VERSION 5.7 ;
BUSBITCHARS "[]" ;
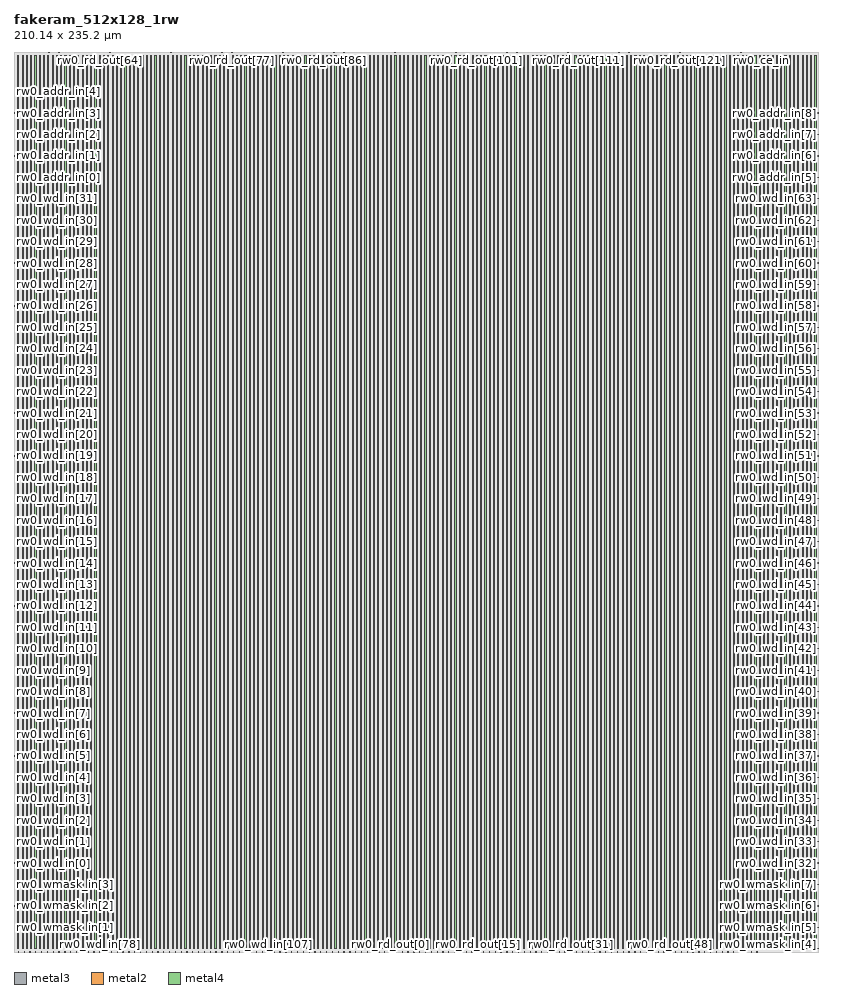
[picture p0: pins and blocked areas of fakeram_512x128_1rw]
MACRO fakeram_512x128_1rw
  FOREIGN fakeram_512x128_1rw 0 0 ;
  SYMMETRY X Y R90 ;
  SIZE 210.140 BY 235.200 ;
  CLASS BLOCK ;
  PIN rw0_wmask_in[0]
    DIRECTION INPUT ;
    USE SIGNAL ;
    SHAPE ABUTMENT ;
    PORT
      LAYER metal3 ;
      RECT 0.000 0.805 0.210 0.875 ;
    END
  END rw0_wmask_in[0]
  PIN rw0_wmask_in[1]
    DIRECTION INPUT ;
    USE SIGNAL ;
    SHAPE ABUTMENT ;
    PORT
      LAYER metal3 ;
      RECT 0.000 6.405 0.210 6.475 ;
    END
  END rw0_wmask_in[1]
  PIN rw0_wmask_in[2]
    DIRECTION INPUT ;
    USE SIGNAL ;
    SHAPE ABUTMENT ;
    PORT
      LAYER metal3 ;
      RECT 0.000 12.005 0.210 12.075 ;
    END
  END rw0_wmask_in[2]
  PIN rw0_wmask_in[3]
    DIRECTION INPUT ;
    USE SIGNAL ;
    SHAPE ABUTMENT ;
    PORT
      LAYER metal3 ;
      RECT 0.000 17.605 0.210 17.675 ;
    END
  END rw0_wmask_in[3]
  PIN rw0_wmask_in[4]
    DIRECTION INPUT ;
    USE SIGNAL ;
    SHAPE ABUTMENT ;
    PORT
      LAYER metal3 ;
      RECT 209.930 0.805 210.140 0.875 ;
    END
  END rw0_wmask_in[4]
  PIN rw0_wmask_in[5]
    DIRECTION INPUT ;
    USE SIGNAL ;
    SHAPE ABUTMENT ;
    PORT
      LAYER metal3 ;
      RECT 209.930 6.405 210.140 6.475 ;
    END
  END rw0_wmask_in[5]
  PIN rw0_wmask_in[6]
    DIRECTION INPUT ;
    USE SIGNAL ;
    SHAPE ABUTMENT ;
    PORT
      LAYER metal3 ;
      RECT 209.930 12.005 210.140 12.075 ;
    END
  END rw0_wmask_in[6]
  PIN rw0_wmask_in[7]
    DIRECTION INPUT ;
    USE SIGNAL ;
    SHAPE ABUTMENT ;
    PORT
      LAYER metal3 ;
      RECT 209.930 17.605 210.140 17.675 ;
    END
  END rw0_wmask_in[7]
  PIN rw0_wmask_in[8]
    DIRECTION INPUT ;
    USE SIGNAL ;
    SHAPE ABUTMENT ;
    PORT
      LAYER metal2 ;
      RECT 1.105 234.990 1.175 235.200 ;
    END
  END rw0_wmask_in[8]
  PIN rw0_wmask_in[9]
    DIRECTION INPUT ;
    USE SIGNAL ;
    SHAPE ABUTMENT ;
    PORT
      LAYER metal2 ;
      RECT 3.765 234.990 3.835 235.200 ;
    END
  END rw0_wmask_in[9]
  PIN rw0_wmask_in[10]
    DIRECTION INPUT ;
    USE SIGNAL ;
    SHAPE ABUTMENT ;
    PORT
      LAYER metal2 ;
      RECT 6.425 234.990 6.495 235.200 ;
    END
  END rw0_wmask_in[10]
  PIN rw0_wmask_in[11]
    DIRECTION INPUT ;
    USE SIGNAL ;
    SHAPE ABUTMENT ;
    PORT
      LAYER metal2 ;
      RECT 9.085 234.990 9.155 235.200 ;
    END
  END rw0_wmask_in[11]
  PIN rw0_wmask_in[12]
    DIRECTION INPUT ;
    USE SIGNAL ;
    SHAPE ABUTMENT ;
    PORT
      LAYER metal2 ;
      RECT 11.745 234.990 11.815 235.200 ;
    END
  END rw0_wmask_in[12]
  PIN rw0_wmask_in[13]
    DIRECTION INPUT ;
    USE SIGNAL ;
    SHAPE ABUTMENT ;
    PORT
      LAYER metal2 ;
      RECT 14.405 234.990 14.475 235.200 ;
    END
  END rw0_wmask_in[13]
  PIN rw0_wmask_in[14]
    DIRECTION INPUT ;
    USE SIGNAL ;
    SHAPE ABUTMENT ;
    PORT
      LAYER metal2 ;
      RECT 17.065 234.990 17.135 235.200 ;
    END
  END rw0_wmask_in[14]
  PIN rw0_wmask_in[15]
    DIRECTION INPUT ;
    USE SIGNAL ;
    SHAPE ABUTMENT ;
    PORT
      LAYER metal2 ;
      RECT 19.725 234.990 19.795 235.200 ;
    END
  END rw0_wmask_in[15]
  PIN rw0_wd_in[0]
    DIRECTION INPUT ;
    USE SIGNAL ;
    SHAPE ABUTMENT ;
    PORT
      LAYER metal3 ;
      RECT 0.000 23.205 0.210 23.275 ;
    END
  END rw0_wd_in[0]
  PIN rw0_wd_in[1]
    DIRECTION INPUT ;
    USE SIGNAL ;
    SHAPE ABUTMENT ;
    PORT
      LAYER metal3 ;
      RECT 0.000 28.805 0.210 28.875 ;
    END
  END rw0_wd_in[1]
  PIN rw0_wd_in[2]
    DIRECTION INPUT ;
    USE SIGNAL ;
    SHAPE ABUTMENT ;
    PORT
      LAYER metal3 ;
      RECT 0.000 34.405 0.210 34.475 ;
    END
  END rw0_wd_in[2]
  PIN rw0_wd_in[3]
    DIRECTION INPUT ;
    USE SIGNAL ;
    SHAPE ABUTMENT ;
    PORT
      LAYER metal3 ;
      RECT 0.000 40.005 0.210 40.075 ;
    END
  END rw0_wd_in[3]
  PIN rw0_wd_in[4]
    DIRECTION INPUT ;
    USE SIGNAL ;
    SHAPE ABUTMENT ;
    PORT
      LAYER metal3 ;
      RECT 0.000 45.605 0.210 45.675 ;
    END
  END rw0_wd_in[4]
  PIN rw0_wd_in[5]
    DIRECTION INPUT ;
    USE SIGNAL ;
    SHAPE ABUTMENT ;
    PORT
      LAYER metal3 ;
      RECT 0.000 51.205 0.210 51.275 ;
    END
  END rw0_wd_in[5]
  PIN rw0_wd_in[6]
    DIRECTION INPUT ;
    USE SIGNAL ;
    SHAPE ABUTMENT ;
    PORT
      LAYER metal3 ;
      RECT 0.000 56.805 0.210 56.875 ;
    END
  END rw0_wd_in[6]
  PIN rw0_wd_in[7]
    DIRECTION INPUT ;
    USE SIGNAL ;
    SHAPE ABUTMENT ;
    PORT
      LAYER metal3 ;
      RECT 0.000 62.405 0.210 62.475 ;
    END
  END rw0_wd_in[7]
  PIN rw0_wd_in[8]
    DIRECTION INPUT ;
    USE SIGNAL ;
    SHAPE ABUTMENT ;
    PORT
      LAYER metal3 ;
      RECT 0.000 68.005 0.210 68.075 ;
    END
  END rw0_wd_in[8]
  PIN rw0_wd_in[9]
    DIRECTION INPUT ;
    USE SIGNAL ;
    SHAPE ABUTMENT ;
    PORT
      LAYER metal3 ;
      RECT 0.000 73.605 0.210 73.675 ;
    END
  END rw0_wd_in[9]
  PIN rw0_wd_in[10]
    DIRECTION INPUT ;
    USE SIGNAL ;
    SHAPE ABUTMENT ;
    PORT
      LAYER metal3 ;
      RECT 0.000 79.205 0.210 79.275 ;
    END
  END rw0_wd_in[10]
  PIN rw0_wd_in[11]
    DIRECTION INPUT ;
    USE SIGNAL ;
    SHAPE ABUTMENT ;
    PORT
      LAYER metal3 ;
      RECT 0.000 84.805 0.210 84.875 ;
    END
  END rw0_wd_in[11]
  PIN rw0_wd_in[12]
    DIRECTION INPUT ;
    USE SIGNAL ;
    SHAPE ABUTMENT ;
    PORT
      LAYER metal3 ;
      RECT 0.000 90.405 0.210 90.475 ;
    END
  END rw0_wd_in[12]
  PIN rw0_wd_in[13]
    DIRECTION INPUT ;
    USE SIGNAL ;
    SHAPE ABUTMENT ;
    PORT
      LAYER metal3 ;
      RECT 0.000 96.005 0.210 96.075 ;
    END
  END rw0_wd_in[13]
  PIN rw0_wd_in[14]
    DIRECTION INPUT ;
    USE SIGNAL ;
    SHAPE ABUTMENT ;
    PORT
      LAYER metal3 ;
      RECT 0.000 101.605 0.210 101.675 ;
    END
  END rw0_wd_in[14]
  PIN rw0_wd_in[15]
    DIRECTION INPUT ;
    USE SIGNAL ;
    SHAPE ABUTMENT ;
    PORT
      LAYER metal3 ;
      RECT 0.000 107.205 0.210 107.275 ;
    END
  END rw0_wd_in[15]
  PIN rw0_wd_in[16]
    DIRECTION INPUT ;
    USE SIGNAL ;
    SHAPE ABUTMENT ;
    PORT
      LAYER metal3 ;
      RECT 0.000 112.805 0.210 112.875 ;
    END
  END rw0_wd_in[16]
  PIN rw0_wd_in[17]
    DIRECTION INPUT ;
    USE SIGNAL ;
    SHAPE ABUTMENT ;
    PORT
      LAYER metal3 ;
      RECT 0.000 118.405 0.210 118.475 ;
    END
  END rw0_wd_in[17]
  PIN rw0_wd_in[18]
    DIRECTION INPUT ;
    USE SIGNAL ;
    SHAPE ABUTMENT ;
    PORT
      LAYER metal3 ;
      RECT 0.000 124.005 0.210 124.075 ;
    END
  END rw0_wd_in[18]
  PIN rw0_wd_in[19]
    DIRECTION INPUT ;
    USE SIGNAL ;
    SHAPE ABUTMENT ;
    PORT
      LAYER metal3 ;
      RECT 0.000 129.605 0.210 129.675 ;
    END
  END rw0_wd_in[19]
  PIN rw0_wd_in[20]
    DIRECTION INPUT ;
    USE SIGNAL ;
    SHAPE ABUTMENT ;
    PORT
      LAYER metal3 ;
      RECT 0.000 135.205 0.210 135.275 ;
    END
  END rw0_wd_in[20]
  PIN rw0_wd_in[21]
    DIRECTION INPUT ;
    USE SIGNAL ;
    SHAPE ABUTMENT ;
    PORT
      LAYER metal3 ;
      RECT 0.000 140.805 0.210 140.875 ;
    END
  END rw0_wd_in[21]
  PIN rw0_wd_in[22]
    DIRECTION INPUT ;
    USE SIGNAL ;
    SHAPE ABUTMENT ;
    PORT
      LAYER metal3 ;
      RECT 0.000 146.405 0.210 146.475 ;
    END
  END rw0_wd_in[22]
  PIN rw0_wd_in[23]
    DIRECTION INPUT ;
    USE SIGNAL ;
    SHAPE ABUTMENT ;
    PORT
      LAYER metal3 ;
      RECT 0.000 152.005 0.210 152.075 ;
    END
  END rw0_wd_in[23]
  PIN rw0_wd_in[24]
    DIRECTION INPUT ;
    USE SIGNAL ;
    SHAPE ABUTMENT ;
    PORT
      LAYER metal3 ;
      RECT 0.000 157.605 0.210 157.675 ;
    END
  END rw0_wd_in[24]
  PIN rw0_wd_in[25]
    DIRECTION INPUT ;
    USE SIGNAL ;
    SHAPE ABUTMENT ;
    PORT
      LAYER metal3 ;
      RECT 0.000 163.205 0.210 163.275 ;
    END
  END rw0_wd_in[25]
  PIN rw0_wd_in[26]
    DIRECTION INPUT ;
    USE SIGNAL ;
    SHAPE ABUTMENT ;
    PORT
      LAYER metal3 ;
      RECT 0.000 168.805 0.210 168.875 ;
    END
  END rw0_wd_in[26]
  PIN rw0_wd_in[27]
    DIRECTION INPUT ;
    USE SIGNAL ;
    SHAPE ABUTMENT ;
    PORT
      LAYER metal3 ;
      RECT 0.000 174.405 0.210 174.475 ;
    END
  END rw0_wd_in[27]
  PIN rw0_wd_in[28]
    DIRECTION INPUT ;
    USE SIGNAL ;
    SHAPE ABUTMENT ;
    PORT
      LAYER metal3 ;
      RECT 0.000 180.005 0.210 180.075 ;
    END
  END rw0_wd_in[28]
  PIN rw0_wd_in[29]
    DIRECTION INPUT ;
    USE SIGNAL ;
    SHAPE ABUTMENT ;
    PORT
      LAYER metal3 ;
      RECT 0.000 185.605 0.210 185.675 ;
    END
  END rw0_wd_in[29]
  PIN rw0_wd_in[30]
    DIRECTION INPUT ;
    USE SIGNAL ;
    SHAPE ABUTMENT ;
    PORT
      LAYER metal3 ;
      RECT 0.000 191.205 0.210 191.275 ;
    END
  END rw0_wd_in[30]
  PIN rw0_wd_in[31]
    DIRECTION INPUT ;
    USE SIGNAL ;
    SHAPE ABUTMENT ;
    PORT
      LAYER metal3 ;
      RECT 0.000 196.805 0.210 196.875 ;
    END
  END rw0_wd_in[31]
  PIN rw0_wd_in[32]
    DIRECTION INPUT ;
    USE SIGNAL ;
    SHAPE ABUTMENT ;
    PORT
      LAYER metal3 ;
      RECT 209.930 23.205 210.140 23.275 ;
    END
  END rw0_wd_in[32]
  PIN rw0_wd_in[33]
    DIRECTION INPUT ;
    USE SIGNAL ;
    SHAPE ABUTMENT ;
    PORT
      LAYER metal3 ;
      RECT 209.930 28.805 210.140 28.875 ;
    END
  END rw0_wd_in[33]
  PIN rw0_wd_in[34]
    DIRECTION INPUT ;
    USE SIGNAL ;
    SHAPE ABUTMENT ;
    PORT
      LAYER metal3 ;
      RECT 209.930 34.405 210.140 34.475 ;
    END
  END rw0_wd_in[34]
  PIN rw0_wd_in[35]
    DIRECTION INPUT ;
    USE SIGNAL ;
    SHAPE ABUTMENT ;
    PORT
      LAYER metal3 ;
      RECT 209.930 40.005 210.140 40.075 ;
    END
  END rw0_wd_in[35]
  PIN rw0_wd_in[36]
    DIRECTION INPUT ;
    USE SIGNAL ;
    SHAPE ABUTMENT ;
    PORT
      LAYER metal3 ;
      RECT 209.930 45.605 210.140 45.675 ;
    END
  END rw0_wd_in[36]
  PIN rw0_wd_in[37]
    DIRECTION INPUT ;
    USE SIGNAL ;
    SHAPE ABUTMENT ;
    PORT
      LAYER metal3 ;
      RECT 209.930 51.205 210.140 51.275 ;
    END
  END rw0_wd_in[37]
  PIN rw0_wd_in[38]
    DIRECTION INPUT ;
    USE SIGNAL ;
    SHAPE ABUTMENT ;
    PORT
      LAYER metal3 ;
      RECT 209.930 56.805 210.140 56.875 ;
    END
  END rw0_wd_in[38]
  PIN rw0_wd_in[39]
    DIRECTION INPUT ;
    USE SIGNAL ;
    SHAPE ABUTMENT ;
    PORT
      LAYER metal3 ;
      RECT 209.930 62.405 210.140 62.475 ;
    END
  END rw0_wd_in[39]
  PIN rw0_wd_in[40]
    DIRECTION INPUT ;
    USE SIGNAL ;
    SHAPE ABUTMENT ;
    PORT
      LAYER metal3 ;
      RECT 209.930 68.005 210.140 68.075 ;
    END
  END rw0_wd_in[40]
  PIN rw0_wd_in[41]
    DIRECTION INPUT ;
    USE SIGNAL ;
    SHAPE ABUTMENT ;
    PORT
      LAYER metal3 ;
      RECT 209.930 73.605 210.140 73.675 ;
    END
  END rw0_wd_in[41]
  PIN rw0_wd_in[42]
    DIRECTION INPUT ;
    USE SIGNAL ;
    SHAPE ABUTMENT ;
    PORT
      LAYER metal3 ;
      RECT 209.930 79.205 210.140 79.275 ;
    END
  END rw0_wd_in[42]
  PIN rw0_wd_in[43]
    DIRECTION INPUT ;
    USE SIGNAL ;
    SHAPE ABUTMENT ;
    PORT
      LAYER metal3 ;
      RECT 209.930 84.805 210.140 84.875 ;
    END
  END rw0_wd_in[43]
  PIN rw0_wd_in[44]
    DIRECTION INPUT ;
    USE SIGNAL ;
    SHAPE ABUTMENT ;
    PORT
      LAYER metal3 ;
      RECT 209.930 90.405 210.140 90.475 ;
    END
  END rw0_wd_in[44]
  PIN rw0_wd_in[45]
    DIRECTION INPUT ;
    USE SIGNAL ;
    SHAPE ABUTMENT ;
    PORT
      LAYER metal3 ;
      RECT 209.930 96.005 210.140 96.075 ;
    END
  END rw0_wd_in[45]
  PIN rw0_wd_in[46]
    DIRECTION INPUT ;
    USE SIGNAL ;
    SHAPE ABUTMENT ;
    PORT
      LAYER metal3 ;
      RECT 209.930 101.605 210.140 101.675 ;
    END
  END rw0_wd_in[46]
  PIN rw0_wd_in[47]
    DIRECTION INPUT ;
    USE SIGNAL ;
    SHAPE ABUTMENT ;
    PORT
      LAYER metal3 ;
      RECT 209.930 107.205 210.140 107.275 ;
    END
  END rw0_wd_in[47]
  PIN rw0_wd_in[48]
    DIRECTION INPUT ;
    USE SIGNAL ;
    SHAPE ABUTMENT ;
    PORT
      LAYER metal3 ;
      RECT 209.930 112.805 210.140 112.875 ;
    END
  END rw0_wd_in[48]
  PIN rw0_wd_in[49]
    DIRECTION INPUT ;
    USE SIGNAL ;
    SHAPE ABUTMENT ;
    PORT
      LAYER metal3 ;
      RECT 209.930 118.405 210.140 118.475 ;
    END
  END rw0_wd_in[49]
  PIN rw0_wd_in[50]
    DIRECTION INPUT ;
    USE SIGNAL ;
    SHAPE ABUTMENT ;
    PORT
      LAYER metal3 ;
      RECT 209.930 124.005 210.140 124.075 ;
    END
  END rw0_wd_in[50]
  PIN rw0_wd_in[51]
    DIRECTION INPUT ;
    USE SIGNAL ;
    SHAPE ABUTMENT ;
    PORT
      LAYER metal3 ;
      RECT 209.930 129.605 210.140 129.675 ;
    END
  END rw0_wd_in[51]
  PIN rw0_wd_in[52]
    DIRECTION INPUT ;
    USE SIGNAL ;
    SHAPE ABUTMENT ;
    PORT
      LAYER metal3 ;
      RECT 209.930 135.205 210.140 135.275 ;
    END
  END rw0_wd_in[52]
  PIN rw0_wd_in[53]
    DIRECTION INPUT ;
    USE SIGNAL ;
    SHAPE ABUTMENT ;
    PORT
      LAYER metal3 ;
      RECT 209.930 140.805 210.140 140.875 ;
    END
  END rw0_wd_in[53]
  PIN rw0_wd_in[54]
    DIRECTION INPUT ;
    USE SIGNAL ;
    SHAPE ABUTMENT ;
    PORT
      LAYER metal3 ;
      RECT 209.930 146.405 210.140 146.475 ;
    END
  END rw0_wd_in[54]
  PIN rw0_wd_in[55]
    DIRECTION INPUT ;
    USE SIGNAL ;
    SHAPE ABUTMENT ;
    PORT
      LAYER metal3 ;
      RECT 209.930 152.005 210.140 152.075 ;
    END
  END rw0_wd_in[55]
  PIN rw0_wd_in[56]
    DIRECTION INPUT ;
    USE SIGNAL ;
    SHAPE ABUTMENT ;
    PORT
      LAYER metal3 ;
      RECT 209.930 157.605 210.140 157.675 ;
    END
  END rw0_wd_in[56]
  PIN rw0_wd_in[57]
    DIRECTION INPUT ;
    USE SIGNAL ;
    SHAPE ABUTMENT ;
    PORT
      LAYER metal3 ;
      RECT 209.930 163.205 210.140 163.275 ;
    END
  END rw0_wd_in[57]
  PIN rw0_wd_in[58]
    DIRECTION INPUT ;
    USE SIGNAL ;
    SHAPE ABUTMENT ;
    PORT
      LAYER metal3 ;
      RECT 209.930 168.805 210.140 168.875 ;
    END
  END rw0_wd_in[58]
  PIN rw0_wd_in[59]
    DIRECTION INPUT ;
    USE SIGNAL ;
    SHAPE ABUTMENT ;
    PORT
      LAYER metal3 ;
      RECT 209.930 174.405 210.140 174.475 ;
    END
  END rw0_wd_in[59]
  PIN rw0_wd_in[60]
    DIRECTION INPUT ;
    USE SIGNAL ;
    SHAPE ABUTMENT ;
    PORT
      LAYER metal3 ;
      RECT 209.930 180.005 210.140 180.075 ;
    END
  END rw0_wd_in[60]
  PIN rw0_wd_in[61]
    DIRECTION INPUT ;
    USE SIGNAL ;
    SHAPE ABUTMENT ;
    PORT
      LAYER metal3 ;
      RECT 209.930 185.605 210.140 185.675 ;
    END
  END rw0_wd_in[61]
  PIN rw0_wd_in[62]
    DIRECTION INPUT ;
    USE SIGNAL ;
    SHAPE ABUTMENT ;
    PORT
      LAYER metal3 ;
      RECT 209.930 191.205 210.140 191.275 ;
    END
  END rw0_wd_in[62]
  PIN rw0_wd_in[63]
    DIRECTION INPUT ;
    USE SIGNAL ;
    SHAPE ABUTMENT ;
    PORT
      LAYER metal3 ;
      RECT 209.930 196.805 210.140 196.875 ;
    END
  END rw0_wd_in[63]
  PIN rw0_wd_in[64]
    DIRECTION INPUT ;
    USE SIGNAL ;
    SHAPE ABUTMENT ;
    PORT
      LAYER metal2 ;
      RECT 1.105 0.000 1.175 0.210 ;
    END
  END rw0_wd_in[64]
  PIN rw0_wd_in[65]
    DIRECTION INPUT ;
    USE SIGNAL ;
    SHAPE ABUTMENT ;
    PORT
      LAYER metal2 ;
      RECT 2.625 0.000 2.695 0.210 ;
    END
  END rw0_wd_in[65]
  PIN rw0_wd_in[66]
    DIRECTION INPUT ;
    USE SIGNAL ;
    SHAPE ABUTMENT ;
    PORT
      LAYER metal2 ;
      RECT 4.145 0.000 4.215 0.210 ;
    END
  END rw0_wd_in[66]
  PIN rw0_wd_in[67]
    DIRECTION INPUT ;
    USE SIGNAL ;
    SHAPE ABUTMENT ;
    PORT
      LAYER metal2 ;
      RECT 5.665 0.000 5.735 0.210 ;
    END
  END rw0_wd_in[67]
  PIN rw0_wd_in[68]
    DIRECTION INPUT ;
    USE SIGNAL ;
    SHAPE ABUTMENT ;
    PORT
      LAYER metal2 ;
      RECT 7.185 0.000 7.255 0.210 ;
    END
  END rw0_wd_in[68]
  PIN rw0_wd_in[69]
    DIRECTION INPUT ;
    USE SIGNAL ;
    SHAPE ABUTMENT ;
    PORT
      LAYER metal2 ;
      RECT 8.705 0.000 8.775 0.210 ;
    END
  END rw0_wd_in[69]
  PIN rw0_wd_in[70]
    DIRECTION INPUT ;
    USE SIGNAL ;
    SHAPE ABUTMENT ;
    PORT
      LAYER metal2 ;
      RECT 10.225 0.000 10.295 0.210 ;
    END
  END rw0_wd_in[70]
  PIN rw0_wd_in[71]
    DIRECTION INPUT ;
    USE SIGNAL ;
    SHAPE ABUTMENT ;
    PORT
      LAYER metal2 ;
      RECT 11.745 0.000 11.815 0.210 ;
    END
  END rw0_wd_in[71]
  PIN rw0_wd_in[72]
    DIRECTION INPUT ;
    USE SIGNAL ;
    SHAPE ABUTMENT ;
    PORT
      LAYER metal2 ;
      RECT 13.265 0.000 13.335 0.210 ;
    END
  END rw0_wd_in[72]
  PIN rw0_wd_in[73]
    DIRECTION INPUT ;
    USE SIGNAL ;
    SHAPE ABUTMENT ;
    PORT
      LAYER metal2 ;
      RECT 14.785 0.000 14.855 0.210 ;
    END
  END rw0_wd_in[73]
  PIN rw0_wd_in[74]
    DIRECTION INPUT ;
    USE SIGNAL ;
    SHAPE ABUTMENT ;
    PORT
      LAYER metal2 ;
      RECT 16.305 0.000 16.375 0.210 ;
    END
  END rw0_wd_in[74]
  PIN rw0_wd_in[75]
    DIRECTION INPUT ;
    USE SIGNAL ;
    SHAPE ABUTMENT ;
    PORT
      LAYER metal2 ;
      RECT 17.825 0.000 17.895 0.210 ;
    END
  END rw0_wd_in[75]
  PIN rw0_wd_in[76]
    DIRECTION INPUT ;
    USE SIGNAL ;
    SHAPE ABUTMENT ;
    PORT
      LAYER metal2 ;
      RECT 19.345 0.000 19.415 0.210 ;
    END
  END rw0_wd_in[76]
  PIN rw0_wd_in[77]
    DIRECTION INPUT ;
    USE SIGNAL ;
    SHAPE ABUTMENT ;
    PORT
      LAYER metal2 ;
      RECT 20.865 0.000 20.935 0.210 ;
    END
  END rw0_wd_in[77]
  PIN rw0_wd_in[78]
    DIRECTION INPUT ;
    USE SIGNAL ;
    SHAPE ABUTMENT ;
    PORT
      LAYER metal2 ;
      RECT 22.385 0.000 22.455 0.210 ;
    END
  END rw0_wd_in[78]
  PIN rw0_wd_in[79]
    DIRECTION INPUT ;
    USE SIGNAL ;
    SHAPE ABUTMENT ;
    PORT
      LAYER metal2 ;
      RECT 23.905 0.000 23.975 0.210 ;
    END
  END rw0_wd_in[79]
  PIN rw0_wd_in[80]
    DIRECTION INPUT ;
    USE SIGNAL ;
    SHAPE ABUTMENT ;
    PORT
      LAYER metal2 ;
      RECT 25.425 0.000 25.495 0.210 ;
    END
  END rw0_wd_in[80]
  PIN rw0_wd_in[81]
    DIRECTION INPUT ;
    USE SIGNAL ;
    SHAPE ABUTMENT ;
    PORT
      LAYER metal2 ;
      RECT 26.945 0.000 27.015 0.210 ;
    END
  END rw0_wd_in[81]
  PIN rw0_wd_in[82]
    DIRECTION INPUT ;
    USE SIGNAL ;
    SHAPE ABUTMENT ;
    PORT
      LAYER metal2 ;
      RECT 28.465 0.000 28.535 0.210 ;
    END
  END rw0_wd_in[82]
  PIN rw0_wd_in[83]
    DIRECTION INPUT ;
    USE SIGNAL ;
    SHAPE ABUTMENT ;
    PORT
      LAYER metal2 ;
      RECT 29.985 0.000 30.055 0.210 ;
    END
  END rw0_wd_in[83]
  PIN rw0_wd_in[84]
    DIRECTION INPUT ;
    USE SIGNAL ;
    SHAPE ABUTMENT ;
    PORT
      LAYER metal2 ;
      RECT 31.505 0.000 31.575 0.210 ;
    END
  END rw0_wd_in[84]
  PIN rw0_wd_in[85]
    DIRECTION INPUT ;
    USE SIGNAL ;
    SHAPE ABUTMENT ;
    PORT
      LAYER metal2 ;
      RECT 33.025 0.000 33.095 0.210 ;
    END
  END rw0_wd_in[85]
  PIN rw0_wd_in[86]
    DIRECTION INPUT ;
    USE SIGNAL ;
    SHAPE ABUTMENT ;
    PORT
      LAYER metal2 ;
      RECT 34.545 0.000 34.615 0.210 ;
    END
  END rw0_wd_in[86]
  PIN rw0_wd_in[87]
    DIRECTION INPUT ;
    USE SIGNAL ;
    SHAPE ABUTMENT ;
    PORT
      LAYER metal2 ;
      RECT 36.065 0.000 36.135 0.210 ;
    END
  END rw0_wd_in[87]
  PIN rw0_wd_in[88]
    DIRECTION INPUT ;
    USE SIGNAL ;
    SHAPE ABUTMENT ;
    PORT
      LAYER metal2 ;
      RECT 37.585 0.000 37.655 0.210 ;
    END
  END rw0_wd_in[88]
  PIN rw0_wd_in[89]
    DIRECTION INPUT ;
    USE SIGNAL ;
    SHAPE ABUTMENT ;
    PORT
      LAYER metal2 ;
      RECT 39.105 0.000 39.175 0.210 ;
    END
  END rw0_wd_in[89]
  PIN rw0_wd_in[90]
    DIRECTION INPUT ;
    USE SIGNAL ;
    SHAPE ABUTMENT ;
    PORT
      LAYER metal2 ;
      RECT 40.625 0.000 40.695 0.210 ;
    END
  END rw0_wd_in[90]
  PIN rw0_wd_in[91]
    DIRECTION INPUT ;
    USE SIGNAL ;
    SHAPE ABUTMENT ;
    PORT
      LAYER metal2 ;
      RECT 42.145 0.000 42.215 0.210 ;
    END
  END rw0_wd_in[91]
  PIN rw0_wd_in[92]
    DIRECTION INPUT ;
    USE SIGNAL ;
    SHAPE ABUTMENT ;
    PORT
      LAYER metal2 ;
      RECT 43.665 0.000 43.735 0.210 ;
    END
  END rw0_wd_in[92]
  PIN rw0_wd_in[93]
    DIRECTION INPUT ;
    USE SIGNAL ;
    SHAPE ABUTMENT ;
    PORT
      LAYER metal2 ;
      RECT 45.185 0.000 45.255 0.210 ;
    END
  END rw0_wd_in[93]
  PIN rw0_wd_in[94]
    DIRECTION INPUT ;
    USE SIGNAL ;
    SHAPE ABUTMENT ;
    PORT
      LAYER metal2 ;
      RECT 46.705 0.000 46.775 0.210 ;
    END
  END rw0_wd_in[94]
  PIN rw0_wd_in[95]
    DIRECTION INPUT ;
    USE SIGNAL ;
    SHAPE ABUTMENT ;
    PORT
      LAYER metal2 ;
      RECT 48.225 0.000 48.295 0.210 ;
    END
  END rw0_wd_in[95]
  PIN rw0_wd_in[96]
    DIRECTION INPUT ;
    USE SIGNAL ;
    SHAPE ABUTMENT ;
    PORT
      LAYER metal2 ;
      RECT 49.745 0.000 49.815 0.210 ;
    END
  END rw0_wd_in[96]
  PIN rw0_wd_in[97]
    DIRECTION INPUT ;
    USE SIGNAL ;
    SHAPE ABUTMENT ;
    PORT
      LAYER metal2 ;
      RECT 51.265 0.000 51.335 0.210 ;
    END
  END rw0_wd_in[97]
  PIN rw0_wd_in[98]
    DIRECTION INPUT ;
    USE SIGNAL ;
    SHAPE ABUTMENT ;
    PORT
      LAYER metal2 ;
      RECT 52.785 0.000 52.855 0.210 ;
    END
  END rw0_wd_in[98]
  PIN rw0_wd_in[99]
    DIRECTION INPUT ;
    USE SIGNAL ;
    SHAPE ABUTMENT ;
    PORT
      LAYER metal2 ;
      RECT 54.305 0.000 54.375 0.210 ;
    END
  END rw0_wd_in[99]
  PIN rw0_wd_in[100]
    DIRECTION INPUT ;
    USE SIGNAL ;
    SHAPE ABUTMENT ;
    PORT
      LAYER metal2 ;
      RECT 55.825 0.000 55.895 0.210 ;
    END
  END rw0_wd_in[100]
  PIN rw0_wd_in[101]
    DIRECTION INPUT ;
    USE SIGNAL ;
    SHAPE ABUTMENT ;
    PORT
      LAYER metal2 ;
      RECT 57.345 0.000 57.415 0.210 ;
    END
  END rw0_wd_in[101]
  PIN rw0_wd_in[102]
    DIRECTION INPUT ;
    USE SIGNAL ;
    SHAPE ABUTMENT ;
    PORT
      LAYER metal2 ;
      RECT 58.865 0.000 58.935 0.210 ;
    END
  END rw0_wd_in[102]
  PIN rw0_wd_in[103]
    DIRECTION INPUT ;
    USE SIGNAL ;
    SHAPE ABUTMENT ;
    PORT
      LAYER metal2 ;
      RECT 60.385 0.000 60.455 0.210 ;
    END
  END rw0_wd_in[103]
  PIN rw0_wd_in[104]
    DIRECTION INPUT ;
    USE SIGNAL ;
    SHAPE ABUTMENT ;
    PORT
      LAYER metal2 ;
      RECT 61.905 0.000 61.975 0.210 ;
    END
  END rw0_wd_in[104]
  PIN rw0_wd_in[105]
    DIRECTION INPUT ;
    USE SIGNAL ;
    SHAPE ABUTMENT ;
    PORT
      LAYER metal2 ;
      RECT 63.425 0.000 63.495 0.210 ;
    END
  END rw0_wd_in[105]
  PIN rw0_wd_in[106]
    DIRECTION INPUT ;
    USE SIGNAL ;
    SHAPE ABUTMENT ;
    PORT
      LAYER metal2 ;
      RECT 64.945 0.000 65.015 0.210 ;
    END
  END rw0_wd_in[106]
  PIN rw0_wd_in[107]
    DIRECTION INPUT ;
    USE SIGNAL ;
    SHAPE ABUTMENT ;
    PORT
      LAYER metal2 ;
      RECT 66.465 0.000 66.535 0.210 ;
    END
  END rw0_wd_in[107]
  PIN rw0_wd_in[108]
    DIRECTION INPUT ;
    USE SIGNAL ;
    SHAPE ABUTMENT ;
    PORT
      LAYER metal2 ;
      RECT 67.985 0.000 68.055 0.210 ;
    END
  END rw0_wd_in[108]
  PIN rw0_wd_in[109]
    DIRECTION INPUT ;
    USE SIGNAL ;
    SHAPE ABUTMENT ;
    PORT
      LAYER metal2 ;
      RECT 69.505 0.000 69.575 0.210 ;
    END
  END rw0_wd_in[109]
  PIN rw0_wd_in[110]
    DIRECTION INPUT ;
    USE SIGNAL ;
    SHAPE ABUTMENT ;
    PORT
      LAYER metal2 ;
      RECT 71.025 0.000 71.095 0.210 ;
    END
  END rw0_wd_in[110]
  PIN rw0_wd_in[111]
    DIRECTION INPUT ;
    USE SIGNAL ;
    SHAPE ABUTMENT ;
    PORT
      LAYER metal2 ;
      RECT 72.545 0.000 72.615 0.210 ;
    END
  END rw0_wd_in[111]
  PIN rw0_wd_in[112]
    DIRECTION INPUT ;
    USE SIGNAL ;
    SHAPE ABUTMENT ;
    PORT
      LAYER metal2 ;
      RECT 74.065 0.000 74.135 0.210 ;
    END
  END rw0_wd_in[112]
  PIN rw0_wd_in[113]
    DIRECTION INPUT ;
    USE SIGNAL ;
    SHAPE ABUTMENT ;
    PORT
      LAYER metal2 ;
      RECT 75.585 0.000 75.655 0.210 ;
    END
  END rw0_wd_in[113]
  PIN rw0_wd_in[114]
    DIRECTION INPUT ;
    USE SIGNAL ;
    SHAPE ABUTMENT ;
    PORT
      LAYER metal2 ;
      RECT 77.105 0.000 77.175 0.210 ;
    END
  END rw0_wd_in[114]
  PIN rw0_wd_in[115]
    DIRECTION INPUT ;
    USE SIGNAL ;
    SHAPE ABUTMENT ;
    PORT
      LAYER metal2 ;
      RECT 78.625 0.000 78.695 0.210 ;
    END
  END rw0_wd_in[115]
  PIN rw0_wd_in[116]
    DIRECTION INPUT ;
    USE SIGNAL ;
    SHAPE ABUTMENT ;
    PORT
      LAYER metal2 ;
      RECT 80.145 0.000 80.215 0.210 ;
    END
  END rw0_wd_in[116]
  PIN rw0_wd_in[117]
    DIRECTION INPUT ;
    USE SIGNAL ;
    SHAPE ABUTMENT ;
    PORT
      LAYER metal2 ;
      RECT 81.665 0.000 81.735 0.210 ;
    END
  END rw0_wd_in[117]
  PIN rw0_wd_in[118]
    DIRECTION INPUT ;
    USE SIGNAL ;
    SHAPE ABUTMENT ;
    PORT
      LAYER metal2 ;
      RECT 83.185 0.000 83.255 0.210 ;
    END
  END rw0_wd_in[118]
  PIN rw0_wd_in[119]
    DIRECTION INPUT ;
    USE SIGNAL ;
    SHAPE ABUTMENT ;
    PORT
      LAYER metal2 ;
      RECT 84.705 0.000 84.775 0.210 ;
    END
  END rw0_wd_in[119]
  PIN rw0_wd_in[120]
    DIRECTION INPUT ;
    USE SIGNAL ;
    SHAPE ABUTMENT ;
    PORT
      LAYER metal2 ;
      RECT 86.225 0.000 86.295 0.210 ;
    END
  END rw0_wd_in[120]
  PIN rw0_wd_in[121]
    DIRECTION INPUT ;
    USE SIGNAL ;
    SHAPE ABUTMENT ;
    PORT
      LAYER metal2 ;
      RECT 87.745 0.000 87.815 0.210 ;
    END
  END rw0_wd_in[121]
  PIN rw0_wd_in[122]
    DIRECTION INPUT ;
    USE SIGNAL ;
    SHAPE ABUTMENT ;
    PORT
      LAYER metal2 ;
      RECT 89.265 0.000 89.335 0.210 ;
    END
  END rw0_wd_in[122]
  PIN rw0_wd_in[123]
    DIRECTION INPUT ;
    USE SIGNAL ;
    SHAPE ABUTMENT ;
    PORT
      LAYER metal2 ;
      RECT 90.785 0.000 90.855 0.210 ;
    END
  END rw0_wd_in[123]
  PIN rw0_wd_in[124]
    DIRECTION INPUT ;
    USE SIGNAL ;
    SHAPE ABUTMENT ;
    PORT
      LAYER metal2 ;
      RECT 92.305 0.000 92.375 0.210 ;
    END
  END rw0_wd_in[124]
  PIN rw0_wd_in[125]
    DIRECTION INPUT ;
    USE SIGNAL ;
    SHAPE ABUTMENT ;
    PORT
      LAYER metal2 ;
      RECT 93.825 0.000 93.895 0.210 ;
    END
  END rw0_wd_in[125]
  PIN rw0_wd_in[126]
    DIRECTION INPUT ;
    USE SIGNAL ;
    SHAPE ABUTMENT ;
    PORT
      LAYER metal2 ;
      RECT 95.345 0.000 95.415 0.210 ;
    END
  END rw0_wd_in[126]
  PIN rw0_wd_in[127]
    DIRECTION INPUT ;
    USE SIGNAL ;
    SHAPE ABUTMENT ;
    PORT
      LAYER metal2 ;
      RECT 96.865 0.000 96.935 0.210 ;
    END
  END rw0_wd_in[127]
  PIN rw0_rd_out[0]
    DIRECTION OUTPUT ;
    USE SIGNAL ;
    SHAPE ABUTMENT ;
    PORT
      LAYER metal2 ;
      RECT 98.385 0.000 98.455 0.210 ;
    END
  END rw0_rd_out[0]
  PIN rw0_rd_out[1]
    DIRECTION OUTPUT ;
    USE SIGNAL ;
    SHAPE ABUTMENT ;
    PORT
      LAYER metal2 ;
      RECT 99.905 0.000 99.975 0.210 ;
    END
  END rw0_rd_out[1]
  PIN rw0_rd_out[2]
    DIRECTION OUTPUT ;
    USE SIGNAL ;
    SHAPE ABUTMENT ;
    PORT
      LAYER metal2 ;
      RECT 101.425 0.000 101.495 0.210 ;
    END
  END rw0_rd_out[2]
  PIN rw0_rd_out[3]
    DIRECTION OUTPUT ;
    USE SIGNAL ;
    SHAPE ABUTMENT ;
    PORT
      LAYER metal2 ;
      RECT 102.945 0.000 103.015 0.210 ;
    END
  END rw0_rd_out[3]
  PIN rw0_rd_out[4]
    DIRECTION OUTPUT ;
    USE SIGNAL ;
    SHAPE ABUTMENT ;
    PORT
      LAYER metal2 ;
      RECT 104.465 0.000 104.535 0.210 ;
    END
  END rw0_rd_out[4]
  PIN rw0_rd_out[5]
    DIRECTION OUTPUT ;
    USE SIGNAL ;
    SHAPE ABUTMENT ;
    PORT
      LAYER metal2 ;
      RECT 105.985 0.000 106.055 0.210 ;
    END
  END rw0_rd_out[5]
  PIN rw0_rd_out[6]
    DIRECTION OUTPUT ;
    USE SIGNAL ;
    SHAPE ABUTMENT ;
    PORT
      LAYER metal2 ;
      RECT 107.505 0.000 107.575 0.210 ;
    END
  END rw0_rd_out[6]
  PIN rw0_rd_out[7]
    DIRECTION OUTPUT ;
    USE SIGNAL ;
    SHAPE ABUTMENT ;
    PORT
      LAYER metal2 ;
      RECT 109.025 0.000 109.095 0.210 ;
    END
  END rw0_rd_out[7]
  PIN rw0_rd_out[8]
    DIRECTION OUTPUT ;
    USE SIGNAL ;
    SHAPE ABUTMENT ;
    PORT
      LAYER metal2 ;
      RECT 110.545 0.000 110.615 0.210 ;
    END
  END rw0_rd_out[8]
  PIN rw0_rd_out[9]
    DIRECTION OUTPUT ;
    USE SIGNAL ;
    SHAPE ABUTMENT ;
    PORT
      LAYER metal2 ;
      RECT 112.065 0.000 112.135 0.210 ;
    END
  END rw0_rd_out[9]
  PIN rw0_rd_out[10]
    DIRECTION OUTPUT ;
    USE SIGNAL ;
    SHAPE ABUTMENT ;
    PORT
      LAYER metal2 ;
      RECT 113.585 0.000 113.655 0.210 ;
    END
  END rw0_rd_out[10]
  PIN rw0_rd_out[11]
    DIRECTION OUTPUT ;
    USE SIGNAL ;
    SHAPE ABUTMENT ;
    PORT
      LAYER metal2 ;
      RECT 115.105 0.000 115.175 0.210 ;
    END
  END rw0_rd_out[11]
  PIN rw0_rd_out[12]
    DIRECTION OUTPUT ;
    USE SIGNAL ;
    SHAPE ABUTMENT ;
    PORT
      LAYER metal2 ;
      RECT 116.625 0.000 116.695 0.210 ;
    END
  END rw0_rd_out[12]
  PIN rw0_rd_out[13]
    DIRECTION OUTPUT ;
    USE SIGNAL ;
    SHAPE ABUTMENT ;
    PORT
      LAYER metal2 ;
      RECT 118.145 0.000 118.215 0.210 ;
    END
  END rw0_rd_out[13]
  PIN rw0_rd_out[14]
    DIRECTION OUTPUT ;
    USE SIGNAL ;
    SHAPE ABUTMENT ;
    PORT
      LAYER metal2 ;
      RECT 119.665 0.000 119.735 0.210 ;
    END
  END rw0_rd_out[14]
  PIN rw0_rd_out[15]
    DIRECTION OUTPUT ;
    USE SIGNAL ;
    SHAPE ABUTMENT ;
    PORT
      LAYER metal2 ;
      RECT 121.185 0.000 121.255 0.210 ;
    END
  END rw0_rd_out[15]
  PIN rw0_rd_out[16]
    DIRECTION OUTPUT ;
    USE SIGNAL ;
    SHAPE ABUTMENT ;
    PORT
      LAYER metal2 ;
      RECT 122.705 0.000 122.775 0.210 ;
    END
  END rw0_rd_out[16]
  PIN rw0_rd_out[17]
    DIRECTION OUTPUT ;
    USE SIGNAL ;
    SHAPE ABUTMENT ;
    PORT
      LAYER metal2 ;
      RECT 124.225 0.000 124.295 0.210 ;
    END
  END rw0_rd_out[17]
  PIN rw0_rd_out[18]
    DIRECTION OUTPUT ;
    USE SIGNAL ;
    SHAPE ABUTMENT ;
    PORT
      LAYER metal2 ;
      RECT 125.745 0.000 125.815 0.210 ;
    END
  END rw0_rd_out[18]
  PIN rw0_rd_out[19]
    DIRECTION OUTPUT ;
    USE SIGNAL ;
    SHAPE ABUTMENT ;
    PORT
      LAYER metal2 ;
      RECT 127.265 0.000 127.335 0.210 ;
    END
  END rw0_rd_out[19]
  PIN rw0_rd_out[20]
    DIRECTION OUTPUT ;
    USE SIGNAL ;
    SHAPE ABUTMENT ;
    PORT
      LAYER metal2 ;
      RECT 128.785 0.000 128.855 0.210 ;
    END
  END rw0_rd_out[20]
  PIN rw0_rd_out[21]
    DIRECTION OUTPUT ;
    USE SIGNAL ;
    SHAPE ABUTMENT ;
    PORT
      LAYER metal2 ;
      RECT 130.305 0.000 130.375 0.210 ;
    END
  END rw0_rd_out[21]
  PIN rw0_rd_out[22]
    DIRECTION OUTPUT ;
    USE SIGNAL ;
    SHAPE ABUTMENT ;
    PORT
      LAYER metal2 ;
      RECT 131.825 0.000 131.895 0.210 ;
    END
  END rw0_rd_out[22]
  PIN rw0_rd_out[23]
    DIRECTION OUTPUT ;
    USE SIGNAL ;
    SHAPE ABUTMENT ;
    PORT
      LAYER metal2 ;
      RECT 133.345 0.000 133.415 0.210 ;
    END
  END rw0_rd_out[23]
  PIN rw0_rd_out[24]
    DIRECTION OUTPUT ;
    USE SIGNAL ;
    SHAPE ABUTMENT ;
    PORT
      LAYER metal2 ;
      RECT 134.865 0.000 134.935 0.210 ;
    END
  END rw0_rd_out[24]
  PIN rw0_rd_out[25]
    DIRECTION OUTPUT ;
    USE SIGNAL ;
    SHAPE ABUTMENT ;
    PORT
      LAYER metal2 ;
      RECT 136.385 0.000 136.455 0.210 ;
    END
  END rw0_rd_out[25]
  PIN rw0_rd_out[26]
    DIRECTION OUTPUT ;
    USE SIGNAL ;
    SHAPE ABUTMENT ;
    PORT
      LAYER metal2 ;
      RECT 137.905 0.000 137.975 0.210 ;
    END
  END rw0_rd_out[26]
  PIN rw0_rd_out[27]
    DIRECTION OUTPUT ;
    USE SIGNAL ;
    SHAPE ABUTMENT ;
    PORT
      LAYER metal2 ;
      RECT 139.425 0.000 139.495 0.210 ;
    END
  END rw0_rd_out[27]
  PIN rw0_rd_out[28]
    DIRECTION OUTPUT ;
    USE SIGNAL ;
    SHAPE ABUTMENT ;
    PORT
      LAYER metal2 ;
      RECT 140.945 0.000 141.015 0.210 ;
    END
  END rw0_rd_out[28]
  PIN rw0_rd_out[29]
    DIRECTION OUTPUT ;
    USE SIGNAL ;
    SHAPE ABUTMENT ;
    PORT
      LAYER metal2 ;
      RECT 142.465 0.000 142.535 0.210 ;
    END
  END rw0_rd_out[29]
  PIN rw0_rd_out[30]
    DIRECTION OUTPUT ;
    USE SIGNAL ;
    SHAPE ABUTMENT ;
    PORT
      LAYER metal2 ;
      RECT 143.985 0.000 144.055 0.210 ;
    END
  END rw0_rd_out[30]
  PIN rw0_rd_out[31]
    DIRECTION OUTPUT ;
    USE SIGNAL ;
    SHAPE ABUTMENT ;
    PORT
      LAYER metal2 ;
      RECT 145.505 0.000 145.575 0.210 ;
    END
  END rw0_rd_out[31]
  PIN rw0_rd_out[32]
    DIRECTION OUTPUT ;
    USE SIGNAL ;
    SHAPE ABUTMENT ;
    PORT
      LAYER metal2 ;
      RECT 147.025 0.000 147.095 0.210 ;
    END
  END rw0_rd_out[32]
  PIN rw0_rd_out[33]
    DIRECTION OUTPUT ;
    USE SIGNAL ;
    SHAPE ABUTMENT ;
    PORT
      LAYER metal2 ;
      RECT 148.545 0.000 148.615 0.210 ;
    END
  END rw0_rd_out[33]
  PIN rw0_rd_out[34]
    DIRECTION OUTPUT ;
    USE SIGNAL ;
    SHAPE ABUTMENT ;
    PORT
      LAYER metal2 ;
      RECT 150.065 0.000 150.135 0.210 ;
    END
  END rw0_rd_out[34]
  PIN rw0_rd_out[35]
    DIRECTION OUTPUT ;
    USE SIGNAL ;
    SHAPE ABUTMENT ;
    PORT
      LAYER metal2 ;
      RECT 151.585 0.000 151.655 0.210 ;
    END
  END rw0_rd_out[35]
  PIN rw0_rd_out[36]
    DIRECTION OUTPUT ;
    USE SIGNAL ;
    SHAPE ABUTMENT ;
    PORT
      LAYER metal2 ;
      RECT 153.105 0.000 153.175 0.210 ;
    END
  END rw0_rd_out[36]
  PIN rw0_rd_out[37]
    DIRECTION OUTPUT ;
    USE SIGNAL ;
    SHAPE ABUTMENT ;
    PORT
      LAYER metal2 ;
      RECT 154.625 0.000 154.695 0.210 ;
    END
  END rw0_rd_out[37]
  PIN rw0_rd_out[38]
    DIRECTION OUTPUT ;
    USE SIGNAL ;
    SHAPE ABUTMENT ;
    PORT
      LAYER metal2 ;
      RECT 156.145 0.000 156.215 0.210 ;
    END
  END rw0_rd_out[38]
  PIN rw0_rd_out[39]
    DIRECTION OUTPUT ;
    USE SIGNAL ;
    SHAPE ABUTMENT ;
    PORT
      LAYER metal2 ;
      RECT 157.665 0.000 157.735 0.210 ;
    END
  END rw0_rd_out[39]
  PIN rw0_rd_out[40]
    DIRECTION OUTPUT ;
    USE SIGNAL ;
    SHAPE ABUTMENT ;
    PORT
      LAYER metal2 ;
      RECT 159.185 0.000 159.255 0.210 ;
    END
  END rw0_rd_out[40]
  PIN rw0_rd_out[41]
    DIRECTION OUTPUT ;
    USE SIGNAL ;
    SHAPE ABUTMENT ;
    PORT
      LAYER metal2 ;
      RECT 160.705 0.000 160.775 0.210 ;
    END
  END rw0_rd_out[41]
  PIN rw0_rd_out[42]
    DIRECTION OUTPUT ;
    USE SIGNAL ;
    SHAPE ABUTMENT ;
    PORT
      LAYER metal2 ;
      RECT 162.225 0.000 162.295 0.210 ;
    END
  END rw0_rd_out[42]
  PIN rw0_rd_out[43]
    DIRECTION OUTPUT ;
    USE SIGNAL ;
    SHAPE ABUTMENT ;
    PORT
      LAYER metal2 ;
      RECT 163.745 0.000 163.815 0.210 ;
    END
  END rw0_rd_out[43]
  PIN rw0_rd_out[44]
    DIRECTION OUTPUT ;
    USE SIGNAL ;
    SHAPE ABUTMENT ;
    PORT
      LAYER metal2 ;
      RECT 165.265 0.000 165.335 0.210 ;
    END
  END rw0_rd_out[44]
  PIN rw0_rd_out[45]
    DIRECTION OUTPUT ;
    USE SIGNAL ;
    SHAPE ABUTMENT ;
    PORT
      LAYER metal2 ;
      RECT 166.785 0.000 166.855 0.210 ;
    END
  END rw0_rd_out[45]
  PIN rw0_rd_out[46]
    DIRECTION OUTPUT ;
    USE SIGNAL ;
    SHAPE ABUTMENT ;
    PORT
      LAYER metal2 ;
      RECT 168.305 0.000 168.375 0.210 ;
    END
  END rw0_rd_out[46]
  PIN rw0_rd_out[47]
    DIRECTION OUTPUT ;
    USE SIGNAL ;
    SHAPE ABUTMENT ;
    PORT
      LAYER metal2 ;
      RECT 169.825 0.000 169.895 0.210 ;
    END
  END rw0_rd_out[47]
  PIN rw0_rd_out[48]
    DIRECTION OUTPUT ;
    USE SIGNAL ;
    SHAPE ABUTMENT ;
    PORT
      LAYER metal2 ;
      RECT 171.345 0.000 171.415 0.210 ;
    END
  END rw0_rd_out[48]
  PIN rw0_rd_out[49]
    DIRECTION OUTPUT ;
    USE SIGNAL ;
    SHAPE ABUTMENT ;
    PORT
      LAYER metal2 ;
      RECT 172.865 0.000 172.935 0.210 ;
    END
  END rw0_rd_out[49]
  PIN rw0_rd_out[50]
    DIRECTION OUTPUT ;
    USE SIGNAL ;
    SHAPE ABUTMENT ;
    PORT
      LAYER metal2 ;
      RECT 174.385 0.000 174.455 0.210 ;
    END
  END rw0_rd_out[50]
  PIN rw0_rd_out[51]
    DIRECTION OUTPUT ;
    USE SIGNAL ;
    SHAPE ABUTMENT ;
    PORT
      LAYER metal2 ;
      RECT 175.905 0.000 175.975 0.210 ;
    END
  END rw0_rd_out[51]
  PIN rw0_rd_out[52]
    DIRECTION OUTPUT ;
    USE SIGNAL ;
    SHAPE ABUTMENT ;
    PORT
      LAYER metal2 ;
      RECT 177.425 0.000 177.495 0.210 ;
    END
  END rw0_rd_out[52]
  PIN rw0_rd_out[53]
    DIRECTION OUTPUT ;
    USE SIGNAL ;
    SHAPE ABUTMENT ;
    PORT
      LAYER metal2 ;
      RECT 178.945 0.000 179.015 0.210 ;
    END
  END rw0_rd_out[53]
  PIN rw0_rd_out[54]
    DIRECTION OUTPUT ;
    USE SIGNAL ;
    SHAPE ABUTMENT ;
    PORT
      LAYER metal2 ;
      RECT 180.465 0.000 180.535 0.210 ;
    END
  END rw0_rd_out[54]
  PIN rw0_rd_out[55]
    DIRECTION OUTPUT ;
    USE SIGNAL ;
    SHAPE ABUTMENT ;
    PORT
      LAYER metal2 ;
      RECT 181.985 0.000 182.055 0.210 ;
    END
  END rw0_rd_out[55]
  PIN rw0_rd_out[56]
    DIRECTION OUTPUT ;
    USE SIGNAL ;
    SHAPE ABUTMENT ;
    PORT
      LAYER metal2 ;
      RECT 183.505 0.000 183.575 0.210 ;
    END
  END rw0_rd_out[56]
  PIN rw0_rd_out[57]
    DIRECTION OUTPUT ;
    USE SIGNAL ;
    SHAPE ABUTMENT ;
    PORT
      LAYER metal2 ;
      RECT 185.025 0.000 185.095 0.210 ;
    END
  END rw0_rd_out[57]
  PIN rw0_rd_out[58]
    DIRECTION OUTPUT ;
    USE SIGNAL ;
    SHAPE ABUTMENT ;
    PORT
      LAYER metal2 ;
      RECT 186.545 0.000 186.615 0.210 ;
    END
  END rw0_rd_out[58]
  PIN rw0_rd_out[59]
    DIRECTION OUTPUT ;
    USE SIGNAL ;
    SHAPE ABUTMENT ;
    PORT
      LAYER metal2 ;
      RECT 188.065 0.000 188.135 0.210 ;
    END
  END rw0_rd_out[59]
  PIN rw0_rd_out[60]
    DIRECTION OUTPUT ;
    USE SIGNAL ;
    SHAPE ABUTMENT ;
    PORT
      LAYER metal2 ;
      RECT 189.585 0.000 189.655 0.210 ;
    END
  END rw0_rd_out[60]
  PIN rw0_rd_out[61]
    DIRECTION OUTPUT ;
    USE SIGNAL ;
    SHAPE ABUTMENT ;
    PORT
      LAYER metal2 ;
      RECT 191.105 0.000 191.175 0.210 ;
    END
  END rw0_rd_out[61]
  PIN rw0_rd_out[62]
    DIRECTION OUTPUT ;
    USE SIGNAL ;
    SHAPE ABUTMENT ;
    PORT
      LAYER metal2 ;
      RECT 192.625 0.000 192.695 0.210 ;
    END
  END rw0_rd_out[62]
  PIN rw0_rd_out[63]
    DIRECTION OUTPUT ;
    USE SIGNAL ;
    SHAPE ABUTMENT ;
    PORT
      LAYER metal2 ;
      RECT 194.145 0.000 194.215 0.210 ;
    END
  END rw0_rd_out[63]
  PIN rw0_rd_out[64]
    DIRECTION OUTPUT ;
    USE SIGNAL ;
    SHAPE ABUTMENT ;
    PORT
      LAYER metal2 ;
      RECT 22.385 234.990 22.455 235.200 ;
    END
  END rw0_rd_out[64]
  PIN rw0_rd_out[65]
    DIRECTION OUTPUT ;
    USE SIGNAL ;
    SHAPE ABUTMENT ;
    PORT
      LAYER metal2 ;
      RECT 25.045 234.990 25.115 235.200 ;
    END
  END rw0_rd_out[65]
  PIN rw0_rd_out[66]
    DIRECTION OUTPUT ;
    USE SIGNAL ;
    SHAPE ABUTMENT ;
    PORT
      LAYER metal2 ;
      RECT 27.705 234.990 27.775 235.200 ;
    END
  END rw0_rd_out[66]
  PIN rw0_rd_out[67]
    DIRECTION OUTPUT ;
    USE SIGNAL ;
    SHAPE ABUTMENT ;
    PORT
      LAYER metal2 ;
      RECT 30.365 234.990 30.435 235.200 ;
    END
  END rw0_rd_out[67]
  PIN rw0_rd_out[68]
    DIRECTION OUTPUT ;
    USE SIGNAL ;
    SHAPE ABUTMENT ;
    PORT
      LAYER metal2 ;
      RECT 33.025 234.990 33.095 235.200 ;
    END
  END rw0_rd_out[68]
  PIN rw0_rd_out[69]
    DIRECTION OUTPUT ;
    USE SIGNAL ;
    SHAPE ABUTMENT ;
    PORT
      LAYER metal2 ;
      RECT 35.685 234.990 35.755 235.200 ;
    END
  END rw0_rd_out[69]
  PIN rw0_rd_out[70]
    DIRECTION OUTPUT ;
    USE SIGNAL ;
    SHAPE ABUTMENT ;
    PORT
      LAYER metal2 ;
      RECT 38.345 234.990 38.415 235.200 ;
    END
  END rw0_rd_out[70]
  PIN rw0_rd_out[71]
    DIRECTION OUTPUT ;
    USE SIGNAL ;
    SHAPE ABUTMENT ;
    PORT
      LAYER metal2 ;
      RECT 41.005 234.990 41.075 235.200 ;
    END
  END rw0_rd_out[71]
  PIN rw0_rd_out[72]
    DIRECTION OUTPUT ;
    USE SIGNAL ;
    SHAPE ABUTMENT ;
    PORT
      LAYER metal2 ;
      RECT 43.665 234.990 43.735 235.200 ;
    END
  END rw0_rd_out[72]
  PIN rw0_rd_out[73]
    DIRECTION OUTPUT ;
    USE SIGNAL ;
    SHAPE ABUTMENT ;
    PORT
      LAYER metal2 ;
      RECT 46.325 234.990 46.395 235.200 ;
    END
  END rw0_rd_out[73]
  PIN rw0_rd_out[74]
    DIRECTION OUTPUT ;
    USE SIGNAL ;
    SHAPE ABUTMENT ;
    PORT
      LAYER metal2 ;
      RECT 48.985 234.990 49.055 235.200 ;
    END
  END rw0_rd_out[74]
  PIN rw0_rd_out[75]
    DIRECTION OUTPUT ;
    USE SIGNAL ;
    SHAPE ABUTMENT ;
    PORT
      LAYER metal2 ;
      RECT 51.645 234.990 51.715 235.200 ;
    END
  END rw0_rd_out[75]
  PIN rw0_rd_out[76]
    DIRECTION OUTPUT ;
    USE SIGNAL ;
    SHAPE ABUTMENT ;
    PORT
      LAYER metal2 ;
      RECT 54.305 234.990 54.375 235.200 ;
    END
  END rw0_rd_out[76]
  PIN rw0_rd_out[77]
    DIRECTION OUTPUT ;
    USE SIGNAL ;
    SHAPE ABUTMENT ;
    PORT
      LAYER metal2 ;
      RECT 56.965 234.990 57.035 235.200 ;
    END
  END rw0_rd_out[77]
  PIN rw0_rd_out[78]
    DIRECTION OUTPUT ;
    USE SIGNAL ;
    SHAPE ABUTMENT ;
    PORT
      LAYER metal2 ;
      RECT 59.625 234.990 59.695 235.200 ;
    END
  END rw0_rd_out[78]
  PIN rw0_rd_out[79]
    DIRECTION OUTPUT ;
    USE SIGNAL ;
    SHAPE ABUTMENT ;
    PORT
      LAYER metal2 ;
      RECT 62.285 234.990 62.355 235.200 ;
    END
  END rw0_rd_out[79]
  PIN rw0_rd_out[80]
    DIRECTION OUTPUT ;
    USE SIGNAL ;
    SHAPE ABUTMENT ;
    PORT
      LAYER metal2 ;
      RECT 64.945 234.990 65.015 235.200 ;
    END
  END rw0_rd_out[80]
  PIN rw0_rd_out[81]
    DIRECTION OUTPUT ;
    USE SIGNAL ;
    SHAPE ABUTMENT ;
    PORT
      LAYER metal2 ;
      RECT 67.605 234.990 67.675 235.200 ;
    END
  END rw0_rd_out[81]
  PIN rw0_rd_out[82]
    DIRECTION OUTPUT ;
    USE SIGNAL ;
    SHAPE ABUTMENT ;
    PORT
      LAYER metal2 ;
      RECT 70.265 234.990 70.335 235.200 ;
    END
  END rw0_rd_out[82]
  PIN rw0_rd_out[83]
    DIRECTION OUTPUT ;
    USE SIGNAL ;
    SHAPE ABUTMENT ;
    PORT
      LAYER metal2 ;
      RECT 72.925 234.990 72.995 235.200 ;
    END
  END rw0_rd_out[83]
  PIN rw0_rd_out[84]
    DIRECTION OUTPUT ;
    USE SIGNAL ;
    SHAPE ABUTMENT ;
    PORT
      LAYER metal2 ;
      RECT 75.585 234.990 75.655 235.200 ;
    END
  END rw0_rd_out[84]
  PIN rw0_rd_out[85]
    DIRECTION OUTPUT ;
    USE SIGNAL ;
    SHAPE ABUTMENT ;
    PORT
      LAYER metal2 ;
      RECT 78.245 234.990 78.315 235.200 ;
    END
  END rw0_rd_out[85]
  PIN rw0_rd_out[86]
    DIRECTION OUTPUT ;
    USE SIGNAL ;
    SHAPE ABUTMENT ;
    PORT
      LAYER metal2 ;
      RECT 80.905 234.990 80.975 235.200 ;
    END
  END rw0_rd_out[86]
  PIN rw0_rd_out[87]
    DIRECTION OUTPUT ;
    USE SIGNAL ;
    SHAPE ABUTMENT ;
    PORT
      LAYER metal2 ;
      RECT 83.565 234.990 83.635 235.200 ;
    END
  END rw0_rd_out[87]
  PIN rw0_rd_out[88]
    DIRECTION OUTPUT ;
    USE SIGNAL ;
    SHAPE ABUTMENT ;
    PORT
      LAYER metal2 ;
      RECT 86.225 234.990 86.295 235.200 ;
    END
  END rw0_rd_out[88]
  PIN rw0_rd_out[89]
    DIRECTION OUTPUT ;
    USE SIGNAL ;
    SHAPE ABUTMENT ;
    PORT
      LAYER metal2 ;
      RECT 88.885 234.990 88.955 235.200 ;
    END
  END rw0_rd_out[89]
  PIN rw0_rd_out[90]
    DIRECTION OUTPUT ;
    USE SIGNAL ;
    SHAPE ABUTMENT ;
    PORT
      LAYER metal2 ;
      RECT 91.545 234.990 91.615 235.200 ;
    END
  END rw0_rd_out[90]
  PIN rw0_rd_out[91]
    DIRECTION OUTPUT ;
    USE SIGNAL ;
    SHAPE ABUTMENT ;
    PORT
      LAYER metal2 ;
      RECT 94.205 234.990 94.275 235.200 ;
    END
  END rw0_rd_out[91]
  PIN rw0_rd_out[92]
    DIRECTION OUTPUT ;
    USE SIGNAL ;
    SHAPE ABUTMENT ;
    PORT
      LAYER metal2 ;
      RECT 96.865 234.990 96.935 235.200 ;
    END
  END rw0_rd_out[92]
  PIN rw0_rd_out[93]
    DIRECTION OUTPUT ;
    USE SIGNAL ;
    SHAPE ABUTMENT ;
    PORT
      LAYER metal2 ;
      RECT 99.525 234.990 99.595 235.200 ;
    END
  END rw0_rd_out[93]
  PIN rw0_rd_out[94]
    DIRECTION OUTPUT ;
    USE SIGNAL ;
    SHAPE ABUTMENT ;
    PORT
      LAYER metal2 ;
      RECT 102.185 234.990 102.255 235.200 ;
    END
  END rw0_rd_out[94]
  PIN rw0_rd_out[95]
    DIRECTION OUTPUT ;
    USE SIGNAL ;
    SHAPE ABUTMENT ;
    PORT
      LAYER metal2 ;
      RECT 104.845 234.990 104.915 235.200 ;
    END
  END rw0_rd_out[95]
  PIN rw0_rd_out[96]
    DIRECTION OUTPUT ;
    USE SIGNAL ;
    SHAPE ABUTMENT ;
    PORT
      LAYER metal2 ;
      RECT 107.505 234.990 107.575 235.200 ;
    END
  END rw0_rd_out[96]
  PIN rw0_rd_out[97]
    DIRECTION OUTPUT ;
    USE SIGNAL ;
    SHAPE ABUTMENT ;
    PORT
      LAYER metal2 ;
      RECT 110.165 234.990 110.235 235.200 ;
    END
  END rw0_rd_out[97]
  PIN rw0_rd_out[98]
    DIRECTION OUTPUT ;
    USE SIGNAL ;
    SHAPE ABUTMENT ;
    PORT
      LAYER metal2 ;
      RECT 112.825 234.990 112.895 235.200 ;
    END
  END rw0_rd_out[98]
  PIN rw0_rd_out[99]
    DIRECTION OUTPUT ;
    USE SIGNAL ;
    SHAPE ABUTMENT ;
    PORT
      LAYER metal2 ;
      RECT 115.485 234.990 115.555 235.200 ;
    END
  END rw0_rd_out[99]
  PIN rw0_rd_out[100]
    DIRECTION OUTPUT ;
    USE SIGNAL ;
    SHAPE ABUTMENT ;
    PORT
      LAYER metal2 ;
      RECT 118.145 234.990 118.215 235.200 ;
    END
  END rw0_rd_out[100]
  PIN rw0_rd_out[101]
    DIRECTION OUTPUT ;
    USE SIGNAL ;
    SHAPE ABUTMENT ;
    PORT
      LAYER metal2 ;
      RECT 120.805 234.990 120.875 235.200 ;
    END
  END rw0_rd_out[101]
  PIN rw0_rd_out[102]
    DIRECTION OUTPUT ;
    USE SIGNAL ;
    SHAPE ABUTMENT ;
    PORT
      LAYER metal2 ;
      RECT 123.465 234.990 123.535 235.200 ;
    END
  END rw0_rd_out[102]
  PIN rw0_rd_out[103]
    DIRECTION OUTPUT ;
    USE SIGNAL ;
    SHAPE ABUTMENT ;
    PORT
      LAYER metal2 ;
      RECT 126.125 234.990 126.195 235.200 ;
    END
  END rw0_rd_out[103]
  PIN rw0_rd_out[104]
    DIRECTION OUTPUT ;
    USE SIGNAL ;
    SHAPE ABUTMENT ;
    PORT
      LAYER metal2 ;
      RECT 128.785 234.990 128.855 235.200 ;
    END
  END rw0_rd_out[104]
  PIN rw0_rd_out[105]
    DIRECTION OUTPUT ;
    USE SIGNAL ;
    SHAPE ABUTMENT ;
    PORT
      LAYER metal2 ;
      RECT 131.445 234.990 131.515 235.200 ;
    END
  END rw0_rd_out[105]
  PIN rw0_rd_out[106]
    DIRECTION OUTPUT ;
    USE SIGNAL ;
    SHAPE ABUTMENT ;
    PORT
      LAYER metal2 ;
      RECT 134.105 234.990 134.175 235.200 ;
    END
  END rw0_rd_out[106]
  PIN rw0_rd_out[107]
    DIRECTION OUTPUT ;
    USE SIGNAL ;
    SHAPE ABUTMENT ;
    PORT
      LAYER metal2 ;
      RECT 136.765 234.990 136.835 235.200 ;
    END
  END rw0_rd_out[107]
  PIN rw0_rd_out[108]
    DIRECTION OUTPUT ;
    USE SIGNAL ;
    SHAPE ABUTMENT ;
    PORT
      LAYER metal2 ;
      RECT 139.425 234.990 139.495 235.200 ;
    END
  END rw0_rd_out[108]
  PIN rw0_rd_out[109]
    DIRECTION OUTPUT ;
    USE SIGNAL ;
    SHAPE ABUTMENT ;
    PORT
      LAYER metal2 ;
      RECT 142.085 234.990 142.155 235.200 ;
    END
  END rw0_rd_out[109]
  PIN rw0_rd_out[110]
    DIRECTION OUTPUT ;
    USE SIGNAL ;
    SHAPE ABUTMENT ;
    PORT
      LAYER metal2 ;
      RECT 144.745 234.990 144.815 235.200 ;
    END
  END rw0_rd_out[110]
  PIN rw0_rd_out[111]
    DIRECTION OUTPUT ;
    USE SIGNAL ;
    SHAPE ABUTMENT ;
    PORT
      LAYER metal2 ;
      RECT 147.405 234.990 147.475 235.200 ;
    END
  END rw0_rd_out[111]
  PIN rw0_rd_out[112]
    DIRECTION OUTPUT ;
    USE SIGNAL ;
    SHAPE ABUTMENT ;
    PORT
      LAYER metal2 ;
      RECT 150.065 234.990 150.135 235.200 ;
    END
  END rw0_rd_out[112]
  PIN rw0_rd_out[113]
    DIRECTION OUTPUT ;
    USE SIGNAL ;
    SHAPE ABUTMENT ;
    PORT
      LAYER metal2 ;
      RECT 152.725 234.990 152.795 235.200 ;
    END
  END rw0_rd_out[113]
  PIN rw0_rd_out[114]
    DIRECTION OUTPUT ;
    USE SIGNAL ;
    SHAPE ABUTMENT ;
    PORT
      LAYER metal2 ;
      RECT 155.385 234.990 155.455 235.200 ;
    END
  END rw0_rd_out[114]
  PIN rw0_rd_out[115]
    DIRECTION OUTPUT ;
    USE SIGNAL ;
    SHAPE ABUTMENT ;
    PORT
      LAYER metal2 ;
      RECT 158.045 234.990 158.115 235.200 ;
    END
  END rw0_rd_out[115]
  PIN rw0_rd_out[116]
    DIRECTION OUTPUT ;
    USE SIGNAL ;
    SHAPE ABUTMENT ;
    PORT
      LAYER metal2 ;
      RECT 160.705 234.990 160.775 235.200 ;
    END
  END rw0_rd_out[116]
  PIN rw0_rd_out[117]
    DIRECTION OUTPUT ;
    USE SIGNAL ;
    SHAPE ABUTMENT ;
    PORT
      LAYER metal2 ;
      RECT 163.365 234.990 163.435 235.200 ;
    END
  END rw0_rd_out[117]
  PIN rw0_rd_out[118]
    DIRECTION OUTPUT ;
    USE SIGNAL ;
    SHAPE ABUTMENT ;
    PORT
      LAYER metal2 ;
      RECT 166.025 234.990 166.095 235.200 ;
    END
  END rw0_rd_out[118]
  PIN rw0_rd_out[119]
    DIRECTION OUTPUT ;
    USE SIGNAL ;
    SHAPE ABUTMENT ;
    PORT
      LAYER metal2 ;
      RECT 168.685 234.990 168.755 235.200 ;
    END
  END rw0_rd_out[119]
  PIN rw0_rd_out[120]
    DIRECTION OUTPUT ;
    USE SIGNAL ;
    SHAPE ABUTMENT ;
    PORT
      LAYER metal2 ;
      RECT 171.345 234.990 171.415 235.200 ;
    END
  END rw0_rd_out[120]
  PIN rw0_rd_out[121]
    DIRECTION OUTPUT ;
    USE SIGNAL ;
    SHAPE ABUTMENT ;
    PORT
      LAYER metal2 ;
      RECT 174.005 234.990 174.075 235.200 ;
    END
  END rw0_rd_out[121]
  PIN rw0_rd_out[122]
    DIRECTION OUTPUT ;
    USE SIGNAL ;
    SHAPE ABUTMENT ;
    PORT
      LAYER metal2 ;
      RECT 176.665 234.990 176.735 235.200 ;
    END
  END rw0_rd_out[122]
  PIN rw0_rd_out[123]
    DIRECTION OUTPUT ;
    USE SIGNAL ;
    SHAPE ABUTMENT ;
    PORT
      LAYER metal2 ;
      RECT 179.325 234.990 179.395 235.200 ;
    END
  END rw0_rd_out[123]
  PIN rw0_rd_out[124]
    DIRECTION OUTPUT ;
    USE SIGNAL ;
    SHAPE ABUTMENT ;
    PORT
      LAYER metal2 ;
      RECT 181.985 234.990 182.055 235.200 ;
    END
  END rw0_rd_out[124]
  PIN rw0_rd_out[125]
    DIRECTION OUTPUT ;
    USE SIGNAL ;
    SHAPE ABUTMENT ;
    PORT
      LAYER metal2 ;
      RECT 184.645 234.990 184.715 235.200 ;
    END
  END rw0_rd_out[125]
  PIN rw0_rd_out[126]
    DIRECTION OUTPUT ;
    USE SIGNAL ;
    SHAPE ABUTMENT ;
    PORT
      LAYER metal2 ;
      RECT 187.305 234.990 187.375 235.200 ;
    END
  END rw0_rd_out[126]
  PIN rw0_rd_out[127]
    DIRECTION OUTPUT ;
    USE SIGNAL ;
    SHAPE ABUTMENT ;
    PORT
      LAYER metal2 ;
      RECT 189.965 234.990 190.035 235.200 ;
    END
  END rw0_rd_out[127]
  PIN rw0_addr_in[0]
    DIRECTION INPUT ;
    USE SIGNAL ;
    SHAPE ABUTMENT ;
    PORT
      LAYER metal3 ;
      RECT 0.000 202.405 0.210 202.475 ;
    END
  END rw0_addr_in[0]
  PIN rw0_addr_in[1]
    DIRECTION INPUT ;
    USE SIGNAL ;
    SHAPE ABUTMENT ;
    PORT
      LAYER metal3 ;
      RECT 0.000 208.005 0.210 208.075 ;
    END
  END rw0_addr_in[1]
  PIN rw0_addr_in[2]
    DIRECTION INPUT ;
    USE SIGNAL ;
    SHAPE ABUTMENT ;
    PORT
      LAYER metal3 ;
      RECT 0.000 213.605 0.210 213.675 ;
    END
  END rw0_addr_in[2]
  PIN rw0_addr_in[3]
    DIRECTION INPUT ;
    USE SIGNAL ;
    SHAPE ABUTMENT ;
    PORT
      LAYER metal3 ;
      RECT 0.000 219.205 0.210 219.275 ;
    END
  END rw0_addr_in[3]
  PIN rw0_addr_in[4]
    DIRECTION INPUT ;
    USE SIGNAL ;
    SHAPE ABUTMENT ;
    PORT
      LAYER metal3 ;
      RECT 0.000 224.805 0.210 224.875 ;
    END
  END rw0_addr_in[4]
  PIN rw0_addr_in[5]
    DIRECTION INPUT ;
    USE SIGNAL ;
    SHAPE ABUTMENT ;
    PORT
      LAYER metal3 ;
      RECT 209.930 202.405 210.140 202.475 ;
    END
  END rw0_addr_in[5]
  PIN rw0_addr_in[6]
    DIRECTION INPUT ;
    USE SIGNAL ;
    SHAPE ABUTMENT ;
    PORT
      LAYER metal3 ;
      RECT 209.930 208.005 210.140 208.075 ;
    END
  END rw0_addr_in[6]
  PIN rw0_addr_in[7]
    DIRECTION INPUT ;
    USE SIGNAL ;
    SHAPE ABUTMENT ;
    PORT
      LAYER metal3 ;
      RECT 209.930 213.605 210.140 213.675 ;
    END
  END rw0_addr_in[7]
  PIN rw0_addr_in[8]
    DIRECTION INPUT ;
    USE SIGNAL ;
    SHAPE ABUTMENT ;
    PORT
      LAYER metal3 ;
      RECT 209.930 219.205 210.140 219.275 ;
    END
  END rw0_addr_in[8]
  PIN rw0_we_in
    DIRECTION INPUT ;
    USE SIGNAL ;
    SHAPE ABUTMENT ;
    PORT
      LAYER metal2 ;
      RECT 192.625 234.990 192.695 235.200 ;
    END
  END rw0_we_in
  PIN rw0_ce_in
    DIRECTION INPUT ;
    USE SIGNAL ;
    SHAPE ABUTMENT ;
    PORT
      LAYER metal2 ;
      RECT 195.285 234.990 195.355 235.200 ;
    END
  END rw0_ce_in
  PIN rw0_clk
    DIRECTION INPUT ;
    USE SIGNAL ;
    SHAPE ABUTMENT ;
    PORT
      LAYER metal2 ;
      RECT 197.945 234.990 198.015 235.200 ;
    END
  END rw0_clk
  PIN VSS
    DIRECTION INOUT ;
    USE GROUND ;
    PORT
      LAYER metal4 ;
      RECT 1.000 0.840 1.280 234.360 ;
      RECT 3.240 0.840 3.520 234.360 ;
      RECT 5.480 0.840 5.760 234.360 ;
      RECT 7.720 0.840 8.000 234.360 ;
      RECT 9.960 0.840 10.240 234.360 ;
      RECT 12.200 0.840 12.480 234.360 ;
      RECT 14.440 0.840 14.720 234.360 ;
      RECT 16.680 0.840 16.960 234.360 ;
      RECT 18.920 0.840 19.200 234.360 ;
      RECT 21.160 0.840 21.440 234.360 ;
      RECT 23.400 0.840 23.680 234.360 ;
      RECT 25.640 0.840 25.920 234.360 ;
      RECT 27.880 0.840 28.160 234.360 ;
      RECT 30.120 0.840 30.400 234.360 ;
      RECT 32.360 0.840 32.640 234.360 ;
      RECT 34.600 0.840 34.880 234.360 ;
      RECT 36.840 0.840 37.120 234.360 ;
      RECT 39.080 0.840 39.360 234.360 ;
      RECT 41.320 0.840 41.600 234.360 ;
      RECT 43.560 0.840 43.840 234.360 ;
      RECT 45.800 0.840 46.080 234.360 ;
      RECT 48.040 0.840 48.320 234.360 ;
      RECT 50.280 0.840 50.560 234.360 ;
      RECT 52.520 0.840 52.800 234.360 ;
      RECT 54.760 0.840 55.040 234.360 ;
      RECT 57.000 0.840 57.280 234.360 ;
      RECT 59.240 0.840 59.520 234.360 ;
      RECT 61.480 0.840 61.760 234.360 ;
      RECT 63.720 0.840 64.000 234.360 ;
      RECT 65.960 0.840 66.240 234.360 ;
      RECT 68.200 0.840 68.480 234.360 ;
      RECT 70.440 0.840 70.720 234.360 ;
      RECT 72.680 0.840 72.960 234.360 ;
      RECT 74.920 0.840 75.200 234.360 ;
      RECT 77.160 0.840 77.440 234.360 ;
      RECT 79.400 0.840 79.680 234.360 ;
      RECT 81.640 0.840 81.920 234.360 ;
      RECT 83.880 0.840 84.160 234.360 ;
      RECT 86.120 0.840 86.400 234.360 ;
      RECT 88.360 0.840 88.640 234.360 ;
      RECT 90.600 0.840 90.880 234.360 ;
      RECT 92.840 0.840 93.120 234.360 ;
      RECT 95.080 0.840 95.360 234.360 ;
      RECT 97.320 0.840 97.600 234.360 ;
      RECT 99.560 0.840 99.840 234.360 ;
      RECT 101.800 0.840 102.080 234.360 ;
      RECT 104.040 0.840 104.320 234.360 ;
      RECT 106.280 0.840 106.560 234.360 ;
      RECT 108.520 0.840 108.800 234.360 ;
      RECT 110.760 0.840 111.040 234.360 ;
      RECT 113.000 0.840 113.280 234.360 ;
      RECT 115.240 0.840 115.520 234.360 ;
      RECT 117.480 0.840 117.760 234.360 ;
      RECT 119.720 0.840 120.000 234.360 ;
      RECT 121.960 0.840 122.240 234.360 ;
      RECT 124.200 0.840 124.480 234.360 ;
      RECT 126.440 0.840 126.720 234.360 ;
      RECT 128.680 0.840 128.960 234.360 ;
      RECT 130.920 0.840 131.200 234.360 ;
      RECT 133.160 0.840 133.440 234.360 ;
      RECT 135.400 0.840 135.680 234.360 ;
      RECT 137.640 0.840 137.920 234.360 ;
      RECT 139.880 0.840 140.160 234.360 ;
      RECT 142.120 0.840 142.400 234.360 ;
      RECT 144.360 0.840 144.640 234.360 ;
      RECT 146.600 0.840 146.880 234.360 ;
      RECT 148.840 0.840 149.120 234.360 ;
      RECT 151.080 0.840 151.360 234.360 ;
      RECT 153.320 0.840 153.600 234.360 ;
      RECT 155.560 0.840 155.840 234.360 ;
      RECT 157.800 0.840 158.080 234.360 ;
      RECT 160.040 0.840 160.320 234.360 ;
      RECT 162.280 0.840 162.560 234.360 ;
      RECT 164.520 0.840 164.800 234.360 ;
      RECT 166.760 0.840 167.040 234.360 ;
      RECT 169.000 0.840 169.280 234.360 ;
      RECT 171.240 0.840 171.520 234.360 ;
      RECT 173.480 0.840 173.760 234.360 ;
      RECT 175.720 0.840 176.000 234.360 ;
      RECT 177.960 0.840 178.240 234.360 ;
      RECT 180.200 0.840 180.480 234.360 ;
      RECT 182.440 0.840 182.720 234.360 ;
      RECT 184.680 0.840 184.960 234.360 ;
      RECT 186.920 0.840 187.200 234.360 ;
      RECT 189.160 0.840 189.440 234.360 ;
      RECT 191.400 0.840 191.680 234.360 ;
      RECT 193.640 0.840 193.920 234.360 ;
      RECT 195.880 0.840 196.160 234.360 ;
      RECT 198.120 0.840 198.400 234.360 ;
      RECT 200.360 0.840 200.640 234.360 ;
      RECT 202.600 0.840 202.880 234.360 ;
      RECT 204.840 0.840 205.120 234.360 ;
      RECT 207.080 0.840 207.360 234.360 ;
      RECT 209.320 0.840 209.600 234.360 ;
    END
  END VSS
  PIN VDD
    DIRECTION INOUT ;
    USE POWER ;
    PORT
      LAYER metal4 ;
      RECT 2.120 0.840 2.400 234.360 ;
      RECT 4.360 0.840 4.640 234.360 ;
      RECT 6.600 0.840 6.880 234.360 ;
      RECT 8.840 0.840 9.120 234.360 ;
      RECT 11.080 0.840 11.360 234.360 ;
      RECT 13.320 0.840 13.600 234.360 ;
      RECT 15.560 0.840 15.840 234.360 ;
      RECT 17.800 0.840 18.080 234.360 ;
      RECT 20.040 0.840 20.320 234.360 ;
      RECT 22.280 0.840 22.560 234.360 ;
      RECT 24.520 0.840 24.800 234.360 ;
      RECT 26.760 0.840 27.040 234.360 ;
      RECT 29.000 0.840 29.280 234.360 ;
      RECT 31.240 0.840 31.520 234.360 ;
      RECT 33.480 0.840 33.760 234.360 ;
      RECT 35.720 0.840 36.000 234.360 ;
      RECT 37.960 0.840 38.240 234.360 ;
      RECT 40.200 0.840 40.480 234.360 ;
      RECT 42.440 0.840 42.720 234.360 ;
      RECT 44.680 0.840 44.960 234.360 ;
      RECT 46.920 0.840 47.200 234.360 ;
      RECT 49.160 0.840 49.440 234.360 ;
      RECT 51.400 0.840 51.680 234.360 ;
      RECT 53.640 0.840 53.920 234.360 ;
      RECT 55.880 0.840 56.160 234.360 ;
      RECT 58.120 0.840 58.400 234.360 ;
      RECT 60.360 0.840 60.640 234.360 ;
      RECT 62.600 0.840 62.880 234.360 ;
      RECT 64.840 0.840 65.120 234.360 ;
      RECT 67.080 0.840 67.360 234.360 ;
      RECT 69.320 0.840 69.600 234.360 ;
      RECT 71.560 0.840 71.840 234.360 ;
      RECT 73.800 0.840 74.080 234.360 ;
      RECT 76.040 0.840 76.320 234.360 ;
      RECT 78.280 0.840 78.560 234.360 ;
      RECT 80.520 0.840 80.800 234.360 ;
      RECT 82.760 0.840 83.040 234.360 ;
      RECT 85.000 0.840 85.280 234.360 ;
      RECT 87.240 0.840 87.520 234.360 ;
      RECT 89.480 0.840 89.760 234.360 ;
      RECT 91.720 0.840 92.000 234.360 ;
      RECT 93.960 0.840 94.240 234.360 ;
      RECT 96.200 0.840 96.480 234.360 ;
      RECT 98.440 0.840 98.720 234.360 ;
      RECT 100.680 0.840 100.960 234.360 ;
      RECT 102.920 0.840 103.200 234.360 ;
      RECT 105.160 0.840 105.440 234.360 ;
      RECT 107.400 0.840 107.680 234.360 ;
      RECT 109.640 0.840 109.920 234.360 ;
      RECT 111.880 0.840 112.160 234.360 ;
      RECT 114.120 0.840 114.400 234.360 ;
      RECT 116.360 0.840 116.640 234.360 ;
      RECT 118.600 0.840 118.880 234.360 ;
      RECT 120.840 0.840 121.120 234.360 ;
      RECT 123.080 0.840 123.360 234.360 ;
      RECT 125.320 0.840 125.600 234.360 ;
      RECT 127.560 0.840 127.840 234.360 ;
      RECT 129.800 0.840 130.080 234.360 ;
      RECT 132.040 0.840 132.320 234.360 ;
      RECT 134.280 0.840 134.560 234.360 ;
      RECT 136.520 0.840 136.800 234.360 ;
      RECT 138.760 0.840 139.040 234.360 ;
      RECT 141.000 0.840 141.280 234.360 ;
      RECT 143.240 0.840 143.520 234.360 ;
      RECT 145.480 0.840 145.760 234.360 ;
      RECT 147.720 0.840 148.000 234.360 ;
      RECT 149.960 0.840 150.240 234.360 ;
      RECT 152.200 0.840 152.480 234.360 ;
      RECT 154.440 0.840 154.720 234.360 ;
      RECT 156.680 0.840 156.960 234.360 ;
      RECT 158.920 0.840 159.200 234.360 ;
      RECT 161.160 0.840 161.440 234.360 ;
      RECT 163.400 0.840 163.680 234.360 ;
      RECT 165.640 0.840 165.920 234.360 ;
      RECT 167.880 0.840 168.160 234.360 ;
      RECT 170.120 0.840 170.400 234.360 ;
      RECT 172.360 0.840 172.640 234.360 ;
      RECT 174.600 0.840 174.880 234.360 ;
      RECT 176.840 0.840 177.120 234.360 ;
      RECT 179.080 0.840 179.360 234.360 ;
      RECT 181.320 0.840 181.600 234.360 ;
      RECT 183.560 0.840 183.840 234.360 ;
      RECT 185.800 0.840 186.080 234.360 ;
      RECT 188.040 0.840 188.320 234.360 ;
      RECT 190.280 0.840 190.560 234.360 ;
      RECT 192.520 0.840 192.800 234.360 ;
      RECT 194.760 0.840 195.040 234.360 ;
      RECT 197.000 0.840 197.280 234.360 ;
      RECT 199.240 0.840 199.520 234.360 ;
      RECT 201.480 0.840 201.760 234.360 ;
      RECT 203.720 0.840 204.000 234.360 ;
      RECT 205.960 0.840 206.240 234.360 ;
      RECT 208.200 0.840 208.480 234.360 ;
    END
  END VDD
  OBS
    LAYER metal1 ;
    RECT 0 0 210.140 235.200 ;
    LAYER metal2 ;
    RECT 0 0 210.140 235.200 ;
    LAYER metal3 ;
    RECT 0 0 210.140 235.200 ;
    LAYER metal4 ;
    RECT 0 0 210.140 235.200 ;
    LAYER OVERLAP ;
    RECT 0 0 210.140 235.200 ;
  END
END fakeram_512x128_1rw

END LIBRARY
